VERSION 5.8 ;
BUSBITCHARS "[]" ;
DIVIDERCHAR "/" ;
UNITS
    DATABASE MICRONS 1000 ;
END UNITS

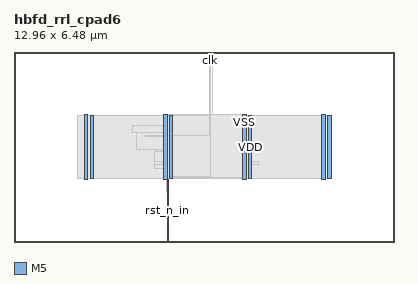
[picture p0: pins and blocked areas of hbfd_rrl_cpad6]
MACRO hbfd_rrl_cpad6
  FOREIGN hbfd_rrl_cpad6 0 0 ;
  CLASS BLOCK ;
  SIZE 12.96 BY 6.48 ;
  PIN clk
    DIRECTION INPUT ;
    USE SIGNAL ;
    PORT
      LAYER M5 ;
        RECT  6.672 6.396 6.696 6.48 ;
    END
  END clk
  PIN rst_n
    DIRECTION OUTPUT ;
    USE SIGNAL ;
    PORT
      LAYER M5 ;
        RECT  6.768 6.396 6.792 6.48 ;
    END
  END rst_n
  PIN rst_n_in
    DIRECTION INPUT ;
    USE SIGNAL ;
    PORT
      LAYER M5 ;
        RECT  5.232 0 5.256 0.084 ;
    END
    PORT
      LAYER M5 ;
        RECT  5.232 0.016 5.256 2.137 ;
    END
  END rst_n_in
  PIN VDD
    DIRECTION INOUT ;
    USE POWER ;
    PORT
      LAYER M5 ;
        RECT  10.692 2.151 10.812 4.329 ;
        RECT  7.992 2.151 8.112 4.329 ;
        RECT  5.292 2.151 5.412 4.329 ;
        RECT  2.592 2.151 2.712 4.329 ;
    END
  END VDD
  PIN VSS
    DIRECTION INOUT ;
    USE GROUND ;
    PORT
      LAYER M5 ;
        RECT  10.5 2.137 10.62 4.343 ;
        RECT  7.8 2.137 7.92 4.343 ;
        RECT  5.1 2.137 5.22 4.343 ;
        RECT  2.4 2.137 2.52 4.343 ;
    END
  END VSS
  # OT_OBS_CLOSED layer=M5 d_um=1.536 added=4
  OBS
    LAYER RVTN ;
     RECT  2.16 2.16 10.8 2.295 ;
     RECT  2.16 2.565 10.8 2.835 ;
     RECT  2.16 3.105 10.8 3.375 ;
     RECT  2.16 3.645 10.8 3.915 ;
     RECT  2.16 4.185 10.8 4.32 ;
    LAYER RVTP ;
     RECT  2.16 2.295 10.8 2.565 ;
     RECT  2.16 2.835 10.8 3.105 ;
     RECT  2.16 3.375 10.8 3.645 ;
     RECT  2.16 3.915 10.8 4.185 ;
    LAYER M1 ;
     RECT  2.16 2.151 10.8 4.329 ;
    LAYER M2 ;
     RECT  2.16 2.151 10.8 4.329 ;
     RECT  10.8 2.421 10.812 4.059 ;
    LAYER M3 ;
     RECT  5.256 1.723 5.274 2.143 ;
     RECT  6.696 2.191 6.714 2.251 ;
     RECT  5.115 2.143 5.274 2.371 ;
     RECT  2.415 2.143 2.505 2.413 ;
     RECT  7.815 2.143 7.905 2.413 ;
     RECT  10.515 2.143 10.605 2.413 ;
     RECT  7.815 2.413 8.097 2.461 ;
     RECT  5.115 2.371 5.49 2.497 ;
     RECT  6.552 2.251 6.714 2.497 ;
     RECT  7.524 2.461 8.097 2.497 ;
     RECT  6.552 2.497 8.097 2.569 ;
     RECT  6.516 2.569 8.097 2.605 ;
     RECT  4.788 2.497 5.562 2.641 ;
     RECT  6.444 2.605 8.097 2.641 ;
     RECT  4.788 2.641 8.334 2.759 ;
     RECT  4.788 2.759 8.097 3.101 ;
     RECT  4.788 3.101 6.93 3.145 ;
     RECT  4.176 3.145 6.93 3.721 ;
     RECT  4.032 3.721 6.93 3.983 ;
     RECT  2.415 2.413 2.697 4.067 ;
     RECT  5.115 3.983 6.93 4.067 ;
     RECT  7.815 3.101 8.097 4.067 ;
     RECT  10.515 2.413 10.797 4.067 ;
     RECT  6.084 4.067 6.93 4.145 ;
     RECT  6.768 4.145 6.93 4.253 ;
     RECT  2.415 4.067 2.505 4.337 ;
     RECT  5.115 4.067 5.205 4.337 ;
     RECT  7.815 4.067 7.905 4.337 ;
     RECT  10.515 4.067 10.605 4.337 ;
     RECT  6.768 4.253 6.786 6.365 ;
    LAYER M4 ;
     RECT  2.408 2.148 2.512 4.332 ;
     RECT  2.512 2.418 2.704 4.062 ;
     RECT  4.489 3.6 5.108 3.624 ;
     RECT  5.108 2.148 5.201 4.332 ;
     RECT  5.201 1.728 5.212 4.332 ;
     RECT  5.212 1.728 5.285 4.062 ;
     RECT  5.285 2.256 5.404 4.062 ;
     RECT  5.404 2.256 6.661 3.72 ;
     RECT  6.661 2.208 6.707 3.72 ;
     RECT  6.707 2.208 6.748 2.76 ;
     RECT  6.716 6.336 6.803 6.36 ;
     RECT  6.748 2.736 7.808 2.76 ;
     RECT  7.808 2.148 7.912 4.332 ;
     RECT  7.912 2.418 8.104 4.062 ;
     RECT  10.508 2.148 10.612 4.332 ;
     RECT  10.612 2.418 10.804 4.062 ;
    LAYER M5 ;
     RECT  2.4 2.137 2.52 2.151 ;
     RECT  5.1 2.137 5.256 2.151 ;
     RECT  7.8 2.137 7.92 2.151 ;
     RECT  10.5 2.137 10.62 2.151 ;
     RECT  5.1 2.151 5.412 2.245 ;
     RECT  6.672 2.197 6.696 2.245 ;
     RECT  5.1 2.245 6.696 3.635 ;
     RECT  2.4 2.151 2.712 4.329 ;
     RECT  5.1 3.635 5.412 4.329 ;
     RECT  7.8 2.151 8.112 4.329 ;
     RECT  10.5 2.151 10.812 4.329 ;
     RECT  2.4 4.329 2.52 4.343 ;
     RECT  5.1 4.329 5.22 4.343 ;
     RECT  7.8 4.329 7.92 4.343 ;
     RECT  10.5 4.329 10.62 4.343 ;
     RECT  6.672 3.635 6.696 6.325 ;
     RECT  6.672 6.325 6.792 6.396 ;
     RECT  6.696 6.396 6.768 6.416 ;
     RECT  5.412 2.197 6.672 2.245 ;
     RECT  6.696 2.197 7.8 4.343 ;
     RECT  5.412 3.635 6.672 4.329 ;
     RECT  5.22 4.329 6.672 4.343 ;
  END
END hbfd_rrl_cpad6
END LIBRARY
